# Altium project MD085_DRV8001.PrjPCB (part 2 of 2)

## Sheet MD085_TCAN284x.SchDoc: TCAN284x-Q1
size 431 x 279 mm; Date: Not shown in title block; ApprovedBy: Not shown in title block; CheckedBy: Not shown in title block; Author: Not shown in title block; CompanyName: Not shown in title block; DrawnBy: Keerthi Kumanan; Engineer: Not shown in title block; Organization: Not shown in title block; Address1: Not shown in title block; Address2: Not shown in title block; Address3: Not shown in title block; Address4: Not shown in title block; DocumentNumber: 1; Revision: Use project parameter SCH_Rev; SheetNumber: 5; SheetTotal: 1; PageSetup: Record=PageOptions¦CenterHorizontal=True¦CenterVertical=True¦PrintScale=1.00¦XCorrection=1.00¦YCorrection=1.00¦PrintKind=0¦BorderSize=5000000¦LeftOffset=0¦BottomOffset=0¦Orientation=2¦PaperLength=1000¦PaperWidth=1000¦Scale=100¦PaperSource=15¦PrintQuality=600¦MediaType=1¦DitherType=10¦PaperKind=Letter¦PrintScaleMode=1

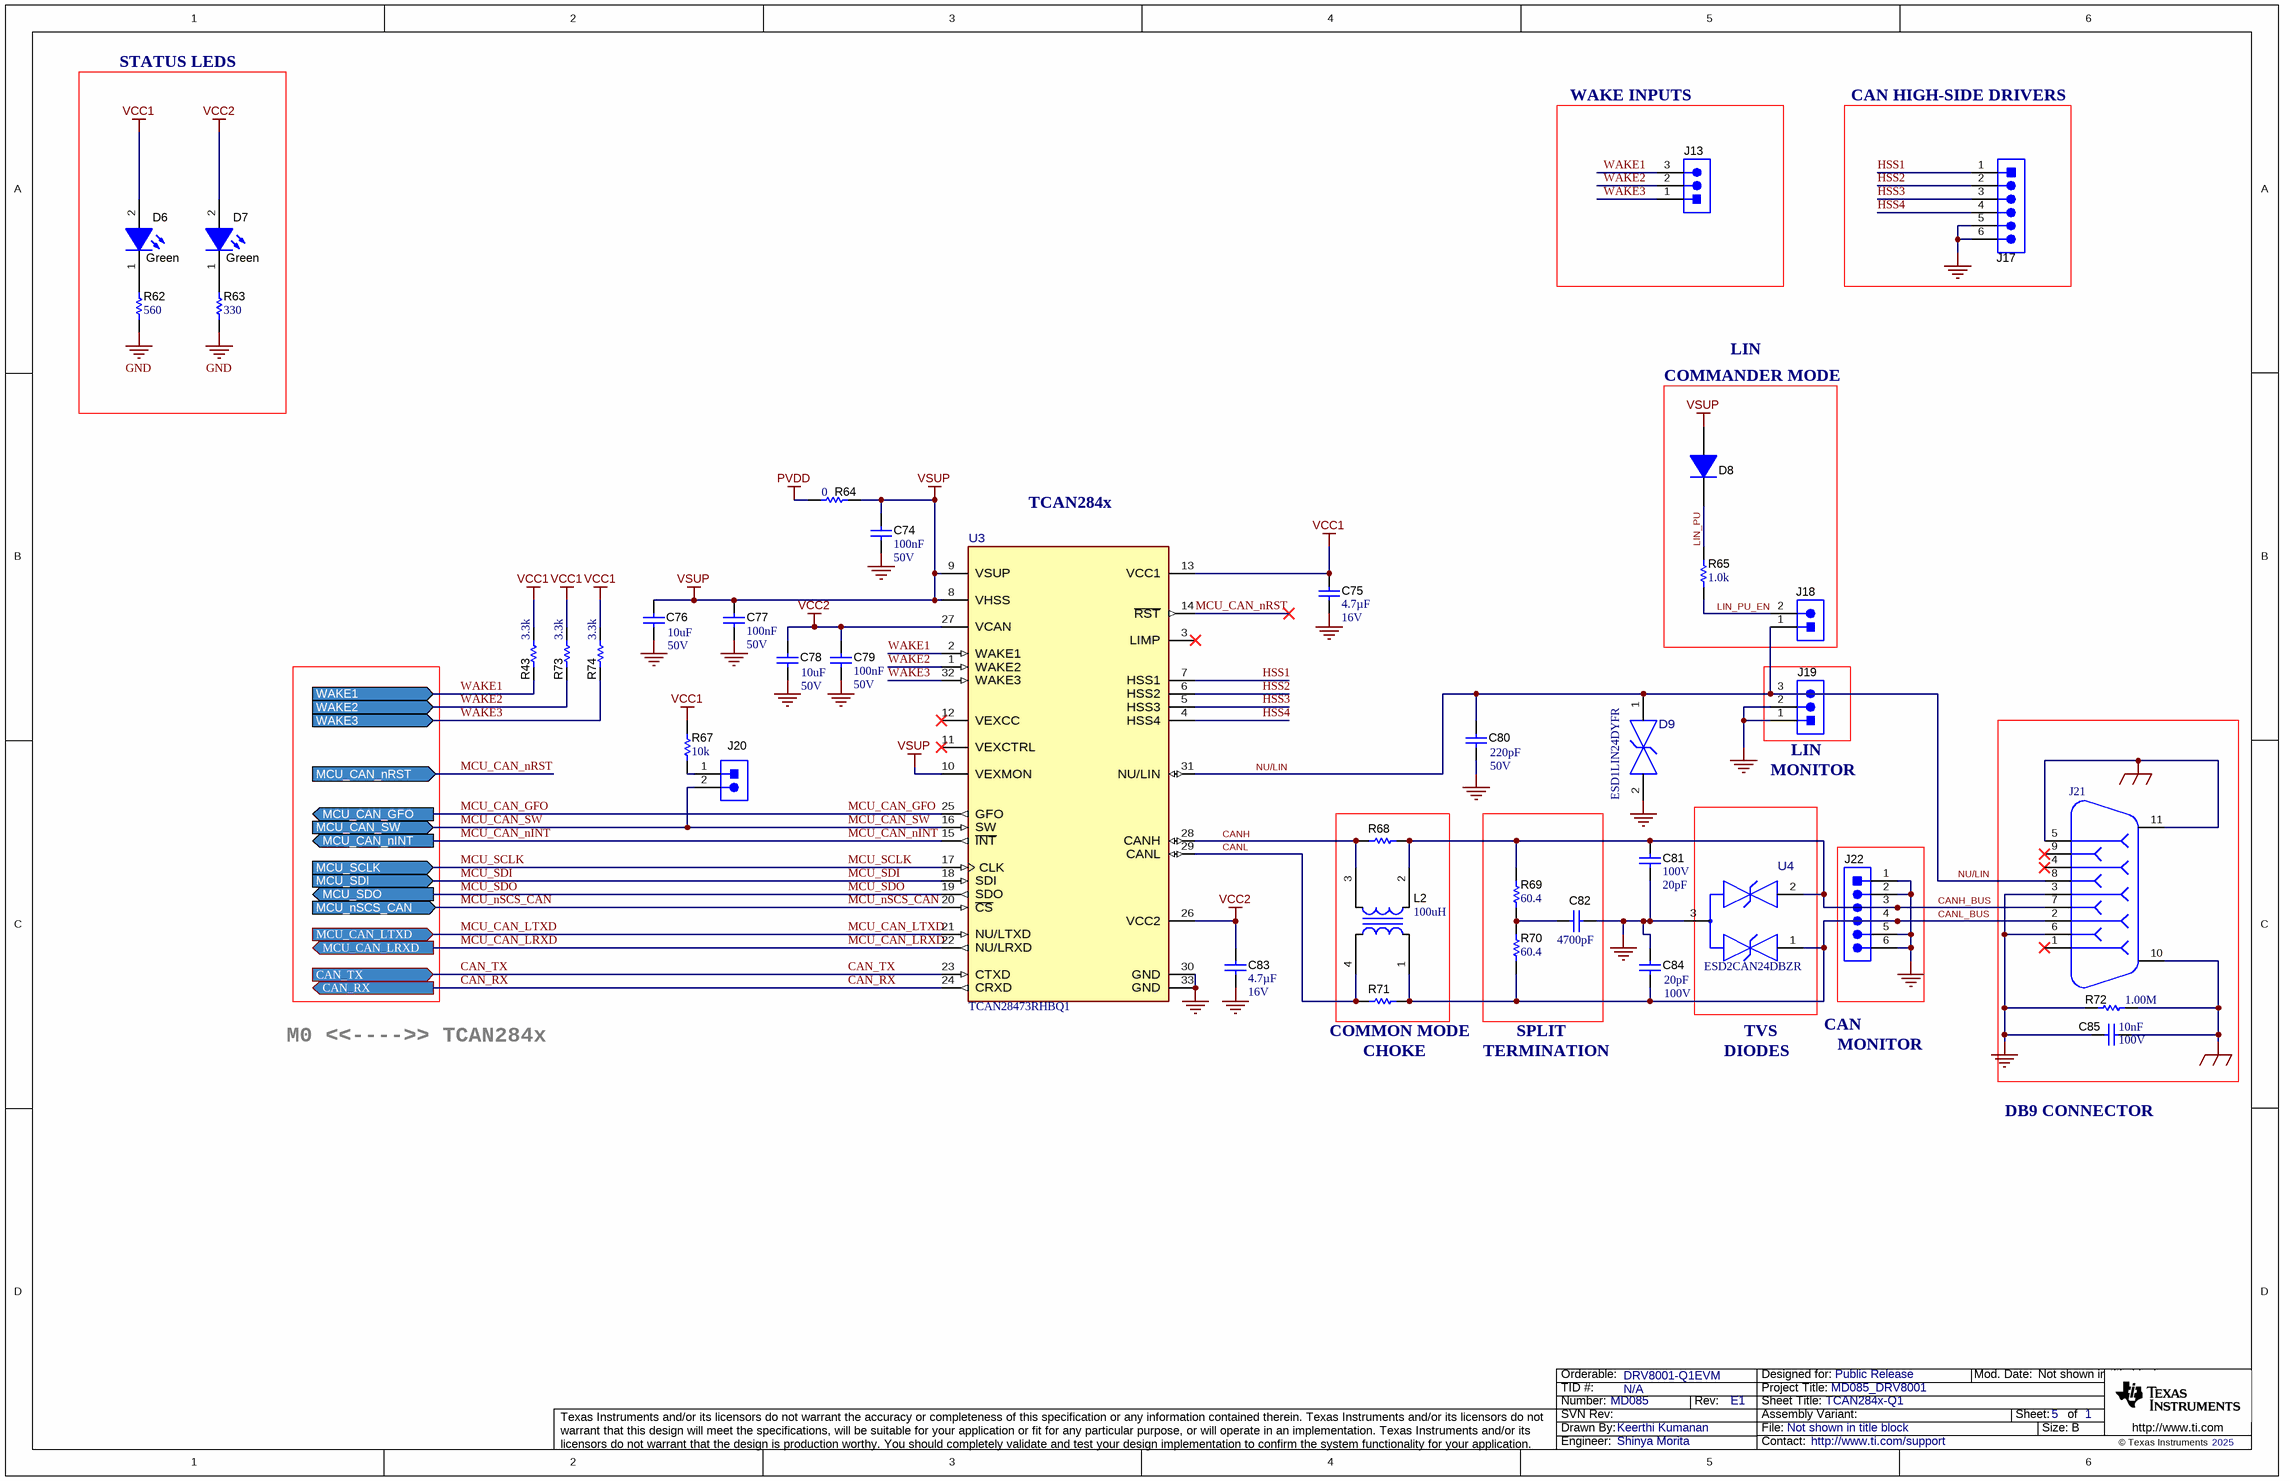
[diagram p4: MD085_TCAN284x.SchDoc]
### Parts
C74  Cap_F: 100nF  VDC_V: 50V  [0603S]  (hidden comment: C1608X7R1H104K080AA)
C75  Cap_F: 4.7µF  VDC_V: 16V  [0805L]  (hidden comment: CGA4J3X7R1C475K125AE)
C76  VDC_V: 50V  ValueDisplayed: 10uF  [1206_180]  (hidden comment: CL31B106KBHNNNE)
C77  Cap_F: 100nF  VDC_V: 50V  [0603S]  (hidden comment: C1608X7R1H104K080AA)
C78  VDC_V: 50V  ValueDisplayed: 10uF  [1206_180]  (hidden comment: CL31B106KBHNNNE)
C79  Cap_F: 100nF  VDC_V: 50V  [0603S]  (hidden comment: C1608X7R1H104K080AA)
C80  Value2: 50V  ValueDisplayed: 220pF  [0603S]  (hidden comment: 06035A221FAT2A)
C81  VDC_V: 100V  ValueDisplayed: 20pF  [0603S]  (hidden comment: GRM1885C2A200JA01D)
C82  ValueDisplayed: 4700pF  [0603S]  (hidden comment: 06031C472KAT2A)
C83  Cap_F: 4.7µF  VDC_V: 16V  [0805L]  (hidden comment: CGA4J3X7R1C475K125AE)
C84  VDC_V: 100V  ValueDisplayed: 20pF  [0603S]  (hidden comment: GRM1885C2A200JA01D)
C85  Cap_F: 10nF  VDC_V: 100V  [0603S]  (hidden comment: C0603X103K1RACTU)
D6  value Green  [WL-SMCW_GREEN]  (hidden comment: 150060VS75000)
D7  value Green  [WL-SMCW_GREEN]  (hidden comment: 150060VS75000)
D8  1N4148W-TP  [SOD-123]  (value not drawn)
D9  ESD1LIN24DYFR  [DYF0002A-MFG]
J13  TSW-103-07-G-S  [TSW-103-07-G-S]  (value not drawn)
J17  TSW-106-07-G-S  [TSW-106-07-G-S]  (value not drawn)
J18  TSW-102-07-G-S  [TSW-102-07-G-S]  (value not drawn)
J19  TSW-103-07-G-S  [TSW-103-07-G-S]  (value not drawn)
J20  TSW-102-07-G-S  [TSW-102-07-G-S]  (value not drawn)
J21  190-009-263R001  [NORCOMP_190-009-263R001]  (value not drawn)
J22  TSW-106-07-G-S  [TSW-106-07-G-S]  (value not drawn)
L2  ValueDisplayed: 100uH  [ACT45B_NoSilk]  (hidden comment: ACT45B-101-2P-TL003)
R43  ValueDisplayed: 3.3k  [0603]  (hidden comment: RC0603JR-073K3L)
R62  ValueDisplayed: 560  [0603]  (hidden comment: RC0603JR-07560RL)
R63  ValueDisplayed: 330  [0603]  (hidden comment: RC0603JR-07330RL)
R64  value 0  [0603]  (hidden comment: Resistor)
R65  ValueDisplayed: 1.0k  [0603]  (hidden comment: RC0603JR-071KL)
R67  ValueDisplayed: 10k  [0603]  (hidden comment: RC0603JR-0710KL)
R68  RC0603JR-070RL  [0603]  (value not drawn)
R69  ValueDisplayed: 60.4  [0603S]  (hidden comment: RC0603FR-0760R4L)
R70  ValueDisplayed: 60.4  [0603S]  (hidden comment: RC0603FR-0760R4L)
R71  RC0603JR-070RL  [0603]  (value not drawn)
R72  ValueDisplayed: 1.00M  [0402S]  (hidden comment: ERJ-2RKF1004X)
R73  ValueDisplayed: 3.3k  [0603]  (hidden comment: RC0603JR-073K3L)
R74  ValueDisplayed: 3.3k  [0603]  (hidden comment: RC0603JR-073K3L)
U3  TCAN28473RHBQ1  [RHB0032U-MFG]
U4  ESD2CAN24DBZR  [DBZ0003A-MFG]

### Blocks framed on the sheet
STATUS LEDS: D6 D7 R62 R63
WAKE INPUTS: J13
CAN HIGH-SIDE DRIVERS: J17
COMMANDER MODE: D8 J18 R65

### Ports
CAN_RX (out), CAN_TX (in), MCU_CAN_GFO (out), MCU_CAN_LRXD (out), MCU_CAN_LTXD (in), MCU_CAN_nINT (out), MCU_CAN_nRST (in), MCU_CAN_SW (in), MCU_nSCS_CAN (in), MCU_SCLK (in), MCU_SDI (in), MCU_SDO (out), WAKE1 (in), WAKE2 (in), WAKE3 (in)

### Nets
GND: C74.2 C75.2 C76.2 C77.2 C78.2 C79.2 C80.2 C81.2 C82.1 C83.2 C84.1 C85.2 D9.2(GND) J17.5 J17.6 J19.1 J19.2 J21.3 J21.6 J22.1 J22.2 J22.5 J22.6 R62.1 R63.1 R72.1 U3.30(GND) U3.33(GND) U4.3(GND)
PVDD: R64.2
SHIELD_GND: C85.1 J21.5 J21.10 J21.11 R72.2
VCC1: C75.1 D6.2(A) R43.2 R67.2 R73.2 R74.2 U3.13(VCC1)
VCC2: C78.1 C79.1 C83.1 D7.2(A) U3.26(VCC2) U3.27(VCAN)
VSUP: C74.1 C76.1 C77.1 D8.2(A) R64.1 U3.8(VHSS) U3.9(VSUP) U3.10(VEXMON)
CAN_RX: U3.24(CRXD) ; port CAN_RX
CAN_TX: U3.23(CTXD) ; port CAN_TX
CANH: L2.3 R68.1 U3.28(CANH)
CANH_BUS: C81.1 J21.7 J22.3 L2.2 R68.2 R69.2 U4.2(2_IO)
CANL: L2.4 R71.1 U3.29(CANL)
CANL_BUS: C84.2 J21.2 J22.4 L2.1 R70.1 R71.2 U4.1(1_IO)
HSS1: J17.1 U3.7(HSS1)
HSS2: J17.2 U3.6(HSS2)
HSS3: J17.3 U3.5(HSS3)
HSS4: J17.4 U3.4(HSS4)
LIN_PU: D8.1(K) R65.1
LIN_PU_EN: J18.2 R65.2
MCU_CAN_GFO: U3.25(GFO) ; port MCU_CAN_GFO
MCU_CAN_LRXD: U3.22(NU/LRXD) ; port MCU_CAN_LRXD
MCU_CAN_LTXD: U3.21(NU/LTXD) ; port MCU_CAN_LTXD
MCU_CAN_nINT: U3.15(~{INT}) ; port MCU_CAN_nINT
MCU_CAN_nRST: U3.14(~{RST}) ; port MCU_CAN_nRST
MCU_CAN_SW: J20.2 U3.16(SW) ; port MCU_CAN_SW
MCU_nSCS_CAN: U3.20(~{CS}) ; port MCU_nSCS_CAN
MCU_SCLK: U3.17(CLK) ; port MCU_SCLK
MCU_SDI: U3.18(SDI) ; port MCU_SDI
MCU_SDO: U3.19(SDO) ; port MCU_SDO
NU/LIN: C80.1 D9.1(IO) J18.1 J19.3 J21.8 U3.31(NU/LIN)
WAKE1: J13.3 R43.1 U3.2(WAKE1) ; port WAKE1
WAKE2: J13.2 R73.1 U3.1(WAKE2) ; port WAKE2
WAKE3: J13.1 R74.1 U3.32(WAKE3) ; port WAKE3
NetC82_2: C82.2 R69.1 R70.2
NetD6_1: D6.1(K) R62.2
NetD7_1: D7.1(K) R63.2
NetJ20_1: J20.1 R67.1

Not connected (* = marked no-connect by the designer): J21 1* 4* 9*; U3 3(LIMP)* 11(VEXCTRL)* 12(VEXCC)*

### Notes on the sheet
- LIN
- TCAN284x
- (near J19) LIN
- (near J19) MONITOR
- CAN
- M0 <<---->> TCAN284x
- (near R71) COMMON MODE
- (near R71) CHOKE
- TERMINATION
- SPLIT
- DIODES
- TVS
- MONITOR
- DB9 CONNECTOR

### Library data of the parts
C74 C77 C79 = CMP-0007044-5: CAP, CERM, 0.1 uF, 50 V, +/- 10%, X7R, 0603; Manufacturer: TDK; TaMin_C: -55°C; ESR_ohm: 29.6m; Polarized: N; SizeAreaWB_mm2: 4.68; Value1: 0.0296 ohm; U/M: EA; Value: 0.1uF; TaMax_C: 125°C; SizeZ_mm: 1; SizeX_mm: 1.6; SizeY_mm: 0.8; Cap_Case: 0603; SizeArea_mm2: 1.28; IRMS_A: 971.99mA; AEC Category: Q200
C75 C83 = CMP-0080701-1: CAP, CERM, 4.7 µF, 16 V,+/- 10%, X7R, AEC-Q200 Grade 1, 0805; Manufacturer: TDK; SizeAreaWB_mm2: 6.75; SizeArea_mm2: 2.5; AEC Qualified: Y; AEC Category: Q200; Value: 4.7uF; TaMax_C: 125°C; SizeZ_mm: 1.45; AEC Grade: 1; Polarized: N; TaMin_C: -55°C; SizeY_mm: 1.25; U/M: EA; SizeX_mm: 2; Cap_Case: 0805
C76 C78 = CMP-0008802-2: CAP, CERM, 10 uF, 50 V, +/- 10%, X7R, 1206; Manufacturer: Samsung; TaMin_C: -55°C; Polarized: N; SizeAreaWB_mm2: 10.92; Value1: Unknown; U/M: EA; Value: 10uF; TaMax_C: 125°C; SizeZ_mm: 1.8; SizeX_mm: 3.2; SizeY_mm: 1.6; Cap_Case: 1206; SizeArea_mm2: 5.12; Cap_F: 10µF; AEC Category: Q200
C80 = CMP-0006776-4: CAP, CERM, 220 pF, 50 V, +/- 1%, C0G/NP0, 0603; Manufacturer: AVX; TaMin_C: -55°C; ESR_ohm: 83m; Polarized: N; SizeAreaWB_mm2: 4.68; Value1: 0.083 ohm; U/M: EA; Value: 220pF; TaMax_C: 125°C; SizeZ_mm: 1; SizeX_mm: 1.6; SizeY_mm: 0.8; Cap_Case: 0603; SizeArea_mm2: 1.28; AEC Category: Q200
C81 C84 = CMP-0007253-4: CAP, CERM, 20 pF, 100 V, +/- 5%, C0G/NP0, 0603; Manufacturer: MuRata; TaMin_C: -55°C; Polarized: N; SizeAreaWB_mm2: 4.68; Value1: Unknown; U/M: EA; Value: 20pF; TaMax_C: 125°C; SizeZ_mm: 1; SizeX_mm: 1.6; SizeY_mm: 0.8; Cap_Case: 0603; SizeArea_mm2: 1.28; AEC Category: Q200
C82 = CMP-0006746-5: CAP, CERM, 4700 pF, 100 V, +/- 10%, X7R, 0603; Manufacturer: AVX; TaMin_C: -55°C; ESR_ohm: 0.136; Polarized: N; SizeAreaWB_mm2: 4.68; Value1: 0.136 ohm; U/M: EA; Value: 4700pF; TaMax_C: 125°C; SizeZ_mm: 1; SizeX_mm: 1.6; SizeY_mm: 0.8; Cap_Case: 0603; Value2: 100V; SizeArea_mm2: 1.28; Cap_F: 4.7nF; AEC Category: Q200
C85 = CMP-0006977-4: CAP, CERM, 0.01 uF, 100 V, +/- 10%, X7R, 0603; Manufacturer: Kemet; TaMin_C: -55°C; Polarized: N; SizeAreaWB_mm2: 4.68; Value1: Unknown; U/M: EA; Value: 0.01uF; TaMax_C: 125°C; SizeZ_mm: 1; SizeX_mm: 1.6; SizeY_mm: 0.8; Cap_Case: 0603; SizeArea_mm2: 1.28; AEC Category: Q200
D6 D7 = CMP-0002894-2: LED, Green, SMD; Manufacturer: Wurth Elektronik; Type: AlInGaP; Value2: 2V; Io_A: 20mA; Value1: W
D8 = CMP-0076974-2: Diode, Switching, 100 V, 0.15 A, SOD-123; Manufacturer: Micro Commercial Components; SizeAreaWB_mm2: 13.095; Vr_V: 100V; SizeArea_mm2: 6.545; TJmax_C: 150°C; AEC Category: Q101; Value: 100V; SizeZ_mm: 1.35; Green_REACh: Incomplete; Io_A: 150mA; Vf_V: 1.25V; SizeY_mm: 1.7; Green_Lifecycle: Not Set; Value1: 0.15A; SizeX_mm: 3.85
D9 = CMP-0098376-1: 24-V, 1-Channel ESD Protection Diode; Manufacturer: Texas Instruments; AEC Qualified: No; SizeZ_mm: 1mm; VRWM: 24V; Ipp: 16A; Ppk: 159.1W; Breakdown Voltage: 25.5V; Cap_F: 2.3pF; Clamping Voltage: 40V; Direction: Bidirectional; Number Of Channels: 1; Standoff Height: 0mm; TaMax_C: +150°C; TaMin_C: -55°C
J13 J19 = CMP-0075407-2: Header, 100mil, 3x1, Gold, TH; Manufacturer: Samtec; Pitch_mm: 2.54; Gender: Male; Cert_CSA: Y; Row_Count: 1; Cert_CULUS: N; Current_A: 6.3A; Green_Lifecycle: Active; Green_REACh: Passed; Voltage_V: 550V
J17 J22 = CMP-0075413-2: Header, 100mil, 6x1, Gold, TH; Manufacturer: Samtec; Pitch_mm: 2.54; Cert_VDE: N; Gender: Male; Cert_CSA: Y; Voltage_V: 550V; Green_REACh: Passed; Current_A: 6.3A; Green_Lifecycle: Active; Row_Count: 1
J18 J20 = CMP-0075405-3: Header, 100mil, 2x1, Gold, TH; Manufacturer: Samtec; Pitch_mm: 2.54; Gender: Male; Cert_CSA: Y; Row_Count: 1; Cert_CULUS: N; Current_A: 6.3A; Green_Lifecycle: Active; Green_REACh: Passed; Voltage_V: 550V
J21 = CMP-0074875-1: Receptacle, D-Sub, 9 Position, R/A, SMT; Manufacturer: NorComp; CNHeader: False; Green_Lifecycle: Not Set; Gender: Female; Green_REACh: Incomplete; Row_Count: 2; ContactFinish: Gold; CT: True
L2 = CMP-0062430-2: Inductor, Ferrite, 100 uH, 0.15 A, 2 ohm, SMD; Manufacturer: TDK; Isat: 0.15A @ % inductance drop; Green_Lifecycle: Active; SizeAreaWB_mm2: 23.1; DCR_ohm: 2; Green_REACh: Passed; Value1: 2 ohm; Value: 100uH; Imax_A: 150mA; SizeZ_mm: 3; SizeX_mm: 4.5; SizeY_mm: 3.2; Value2: 0.15A; SizeArea_mm2: 14.4; Ind_H: 100µH; AEC Category: Q200
R43 R73 R74 = CMP-0025918-5: RES, 3.3 k, 5%, 0.1 W, 0603; Manufacturer: Yageo; Power_W: 100mW; TempCo: 100 ppm/C; Value_Code: 3k30; Value: 3.3k; SizeX_mm: 1.6; SizeY_mm: 0.8; SizeZ_mm: 1; Value2: 0.1W; SizeArea_mm2: 1.28; AEC Qualified: N; VDC_V: 75V; AEC Category: Q200; EIA_Code: E24; SizeAreaWB_mm2: 4.68
R62 = CMP-0025930-5: RES, 560, 5%, 0.1 W, 0603; Manufacturer: Yageo; Power_W: 100mW; TempCo: 100 ppm/C; Value_Code: 560R; Value: 560; EIA_Code: E24; SizeX_mm: 1.6; SizeY_mm: 0.8; SizeZ_mm: 1; Value2: 0.1W; SizeArea_mm2: 1.28; AEC Qualified: N; VDC_V: 75V; AEC Category: Q200; SizeAreaWB_mm2: 4.68
R63 = CMP-0025912-5: RES, 330, 5%, 0.1 W, 0603; Manufacturer: Yageo; Power_W: 100mW; TempCo: 100 ppm/C; Value_Code: 330R; Value: 330; EIA_Code: E24; SizeX_mm: 1.6; SizeY_mm: 0.8; SizeZ_mm: 1; Value2: 0.1W; SizeArea_mm2: 1.28; AEC Qualified: N; VDC_V: 75V; AEC Category: Q200; SizeAreaWB_mm2: 4.68
R64 = CMP-0025885-5: RES, 0, 5%, 0.1 W, 0603; PartNumber: RC0603JR-070RL; Manufacturer: Yageo; Power_W: 100mW; VDC_V: 75V; AEC Qualified: N; SizeZ_mm: 1; AEC Category: Q200; EIA_Code: E24; SizeArea_mm2: 1.28; SizeAreaWB_mm2: 4.68; SizeX_mm: 1.6; SizeY_mm: 0.8; TempCo: 200 ppm/C; Value2: 0.1W; Value_Code: 0000
R65 = CMP-0025899-5: RES, 1.0 k, 5%, 0.1 W, 0603; Manufacturer: Yageo; Power_W: 100mW; TempCo: 100 ppm/C; Value_Code: 1k00; Value: 1.0k; EIA_Code: E24; Res_ohm: 1k; SizeX_mm: 1.6; SizeY_mm: 0.8; SizeZ_mm: 1; Value2: 0.1W; SizeArea_mm2: 1.28; AEC Qualified: N; VDC_V: 75V; AEC Category: Q200; SizeAreaWB_mm2: 4.68
R67 = CMP-0025886-5: RES, 10 k, 5%, 0.1 W, 0603; Manufacturer: Yageo; Value: 10k; SizeY_mm: 0.8; SizeArea_mm2: 1.28; EIA_Code: E24; Power_W: 100mW; SizeX_mm: 1.6; Value2: 0.1W; Value_Code: 10k0; VDC_V: 75V; SizeZ_mm: 1; AEC Qualified: N; AEC Category: Q200; TempCo: 100 ppm/C; SizeAreaWB_mm2: 4.68
R68 R71 = CMP-0025885-5: RES, 0, 5%, 0.1 W, 0603; Manufacturer: Yageo; AEC Qualified: N; Res_ohm: 0; Value: 0; SizeZ_mm: 1; Power_W: 100mW; VDC_V: 75V; AEC Category: Q200; EIA_Code: E24; SizeArea_mm2: 1.28; SizeAreaWB_mm2: 4.68; SizeX_mm: 1.6; SizeY_mm: 0.8; TempCo: 200 ppm/C; Value2: 0.1W; Value_Code: 0000
R69 R70 = CMP-0023213-5: RES, 60.4, 1%, 0.1 W, 0603; Manufacturer: Yageo; Power_W: 100mW; TempCo: 100 ppm/C; Value_Code: 60R4; Value: 60.4; EIA_Code: E96; SizeX_mm: 1.6; SizeY_mm: 0.8; SizeZ_mm: 1; Value2: 0.1W; SizeArea_mm2: 1.28; AEC Qualified: N; VDC_V: 75V; AEC Category: Q200; SizeAreaWB_mm2: 4.68
R72 = CMP-0026660-1: RES, 1.00 M, 1%, 0.1 W, 0402; Manufacturer: Panasonic; Power_W: 100mW; TempCo: 100 ppm/C; Value_Code: 1M00; U/M: EA; Value: 1.00Meg; EIA_Code: E96; Res_ohm: 1M; SizeX_mm: 1; SizeY_mm: 0.5; SizeZ_mm: 0.6; Value2: 0.1W; VDC_V: 50V; AEC Category: Q200
U3 = CMP-0093295-1: CAN FD and LIN System Basis Chip (SBC) with Integrated Watchdog, Selective Wake and Advanced CAN Bus Fault Diagnostics; Manufacturer: Texas Instruments; TJmax_C: +150°C; Min Supply Voltage: 4.5V; Interface: SPI,CAN,LIN; Standoff Height: 0mm; AEC Grade: Grade 1; SizeZ_mm: 1mm; Max Supply Voltage: 28V; AEC Qualified: Yes
U4 = CMP-0093261-1: 24-V, 2-Channel ESD Protection Diode for In-Vehicle Networks; Manufacturer: Texas Instruments; Cap_F: 3pF; Breakdown Voltage: 25.5V; Clamping Voltage: 32V; TaMax_C: +150°C; Direction: Bidirectional; TaMin_C: -55°C; Ipp: 3.5A; VRWM: 24V; Standoff Height: 0.01mm; SizeZ_mm: 1.12mm; Ppk: 147W; AEC Qualified: No; Number Of Channels: 2

## Sheet MD085_DRV800x.SchDoc: DRV800x-Q1
size 431 x 279 mm; VersionControl_RevNumber: 1; Date: Not shown in title block; ApprovedBy: Not shown in title block; CheckedBy: Not shown in title block; Author: Not shown in title block; CompanyName: Not shown in title block; DrawnBy: Keerthi Kumanan; Engineer: Not shown in title block; Organization: Not shown in title block; Address1: Not shown in title block; Address2: Not shown in title block; Address3: Not shown in title block; Address4: Not shown in title block; DocumentNumber: 1; Revision: 1; SheetNumber: 4; SheetTotal: 1; PageSetup: Record=PageOptions¦CenterHorizontal=True¦CenterVertical=True¦PrintScale=1.00¦XCorrection=1.00¦YCorrection=1.00¦PrintKind=0¦BorderSize=5000000¦LeftOffset=0¦BottomOffset=0¦Orientation=2¦PaperLength=1000¦PaperWidth=1000¦Scale=100¦PaperSource=15¦PrintQuality=600¦MediaType=1¦DitherType=10¦PaperKind=Letter¦PrintScaleMode=1; VersionControl_ProjFolderRevNumber: 1; VersionControl_RevNumberShort: 1; VersionControl_ProjFolderRevNumberShort: 1

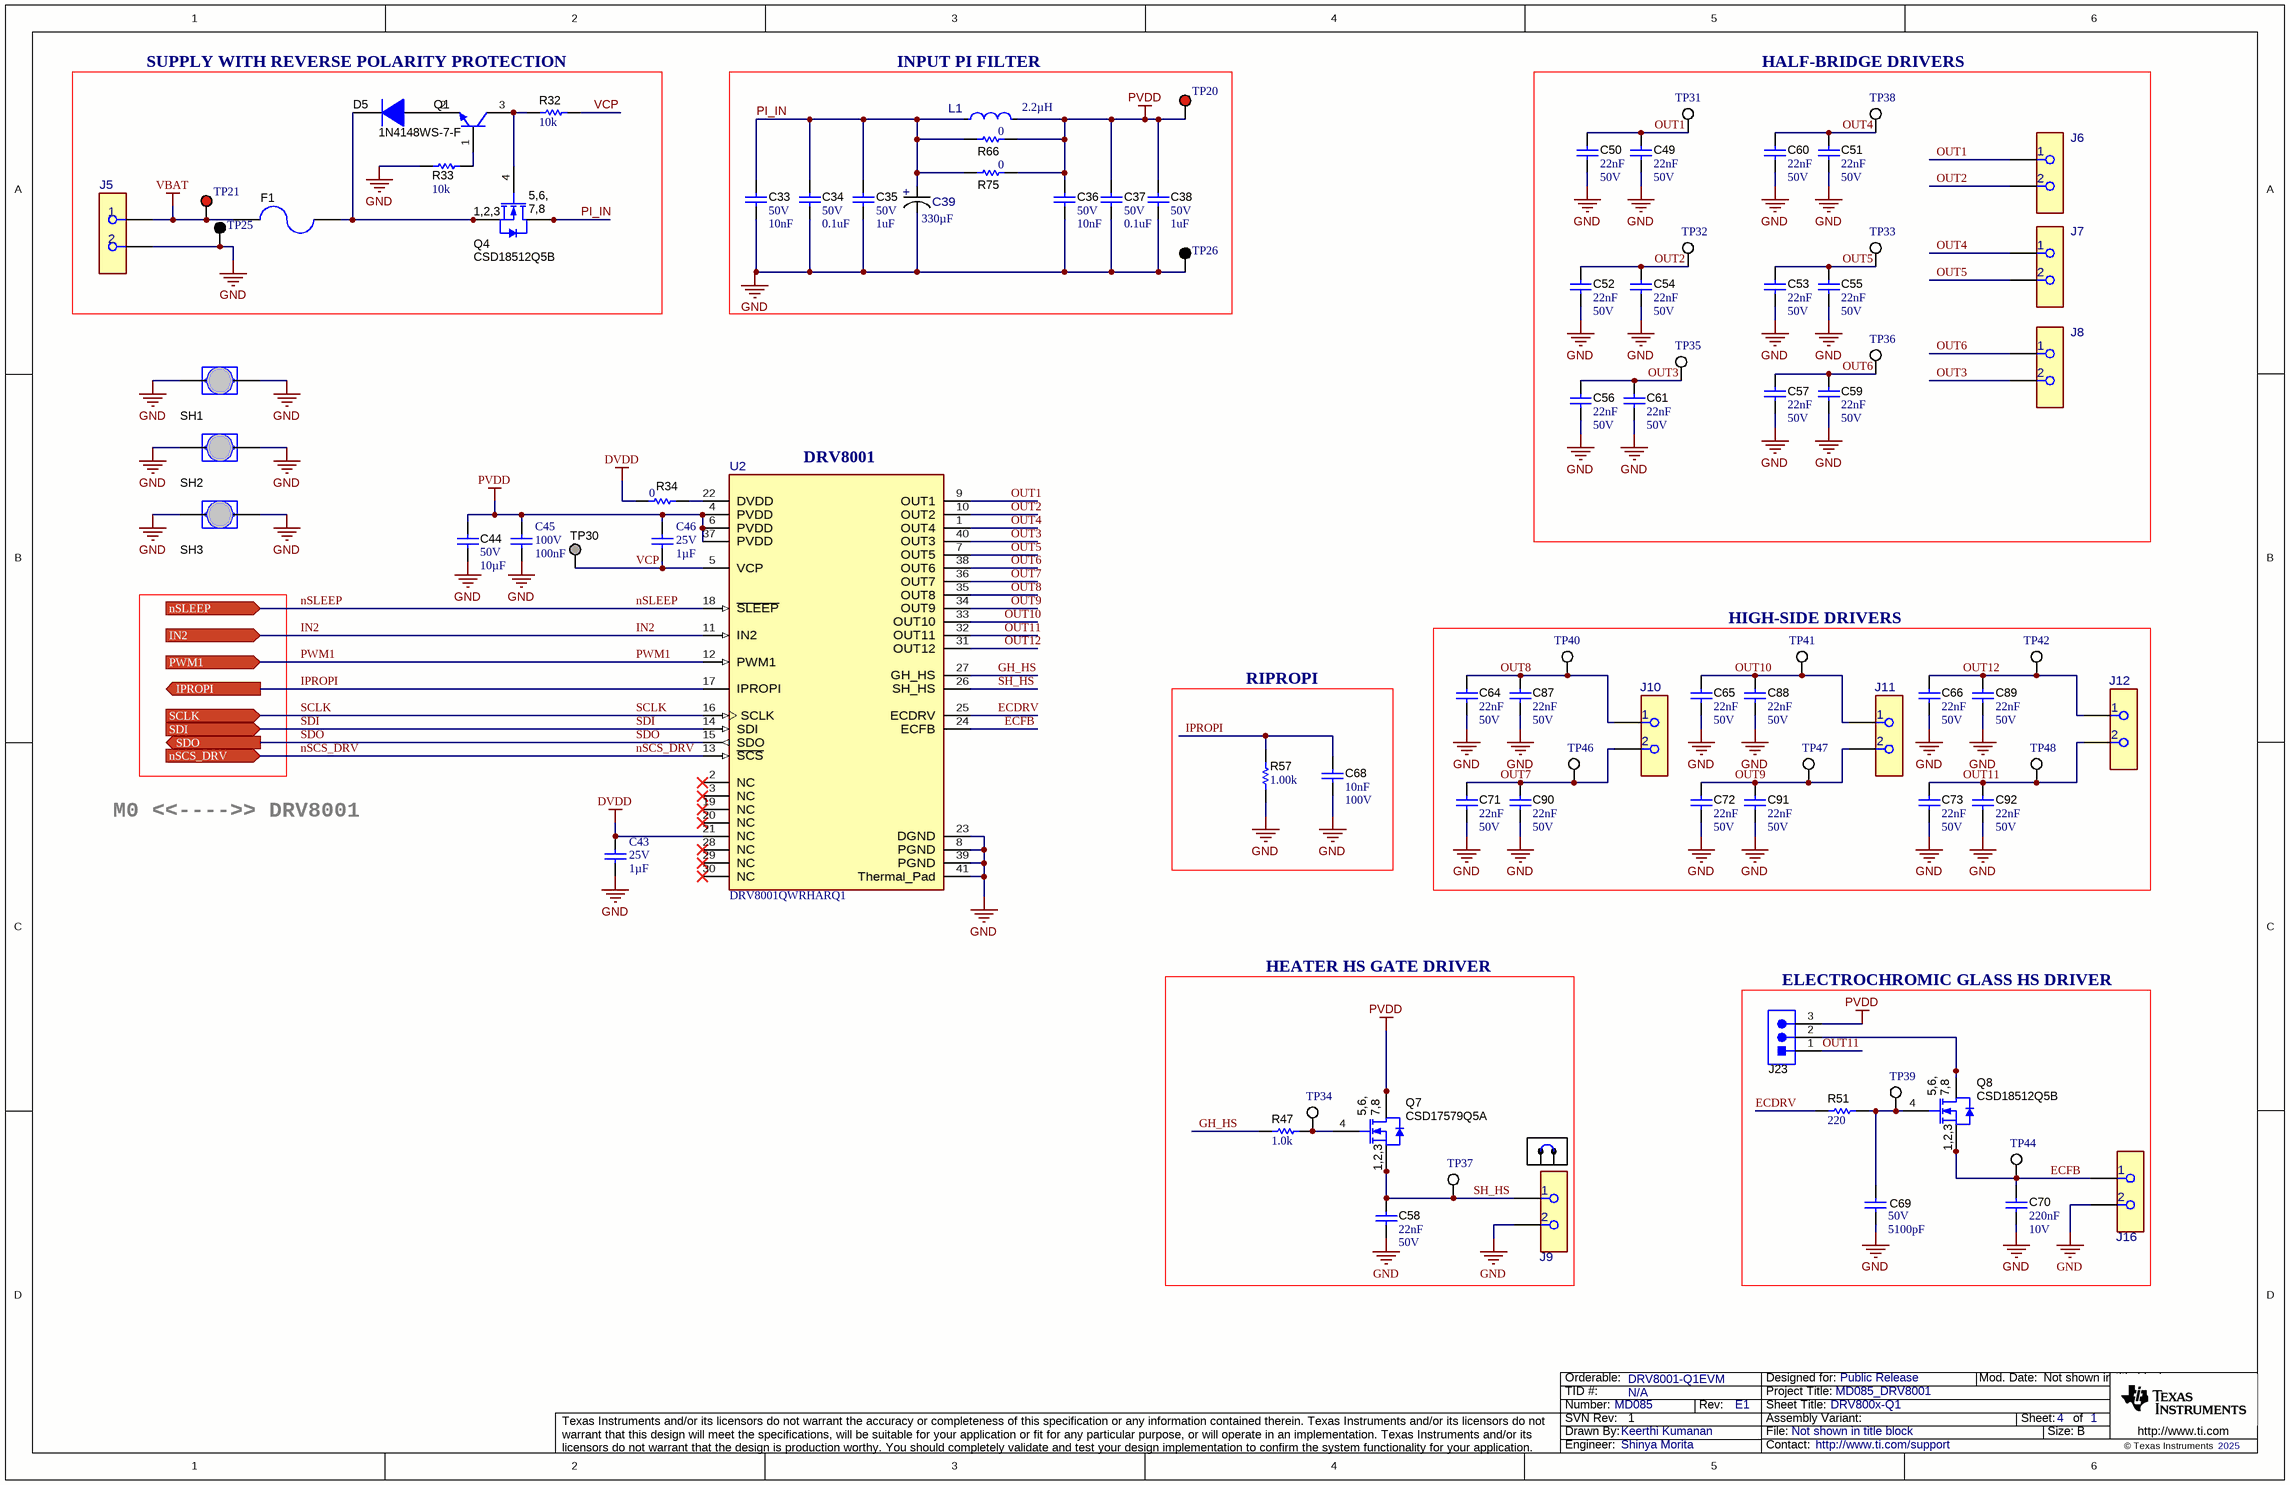
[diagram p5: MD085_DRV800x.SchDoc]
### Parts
C33  VDC_V: 50V  Cap_F: 10nF  [0603L]  (hidden comment: 885012206089)
C34  VDC_V: 50V  ValueDisplayed: 0.1uF  [0603]  (hidden comment: 885012206095)
C35  VDC_V: 50V  ValueDisplayed: 1uF  [0805L]  (hidden comment: 885012207103)
C36  VDC_V: 50V  Cap_F: 10nF  [0603L]  (hidden comment: 885012206089)
C37  VDC_V: 50V  ValueDisplayed: 0.1uF  [0603]  (hidden comment: 885012206095)
C38  VDC_V: 50V  ValueDisplayed: 1uF  [0805L]  (hidden comment: 885012207103)
C39  Cap_F: 330µF  [FP-860020675021_RADIAL-MFG]  (hidden comment: 860020675021)
C43  value 1µF  Rated Voltage (DC): 25V  [WCAP-CSGP_0603_L1.6W0.8H0.8_Reflow]  (hidden comment: 885012206076)
C44  VDC_V: 50V  ValueDisplayed: 10µF  [1206_180]  (hidden comment: 885012108022)
C45  value 100nF  Rated Voltage (DC): 100V  [WCAP-CSGP_0603_L1.6W0.8H0.8_Reflow]  (hidden comment: 885012206120)
C46  value 1µF  Rated Voltage (DC): 25V  [WCAP-CSGP_0603_L1.6W0.8H0.8_Reflow]  (hidden comment: 885012206076)
C49  Cap_F: 22nF  VDC_V: 50V  [0603]  (hidden comment: 885012206091)
C50  Cap_F: 22nF  VDC_V: 50V  [0603]  (hidden comment: 885012206091)
C51  Cap_F: 22nF  VDC_V: 50V  [0603]  (hidden comment: 885012206091)
C52  Cap_F: 22nF  VDC_V: 50V  [0603]  (hidden comment: 885012206091)
C53  Cap_F: 22nF  VDC_V: 50V  [0603]  (hidden comment: 885012206091)
C54  Cap_F: 22nF  VDC_V: 50V  [0603]  (hidden comment: 885012206091)
C55  Cap_F: 22nF  VDC_V: 50V  [0603]  (hidden comment: 885012206091)
C56  Cap_F: 22nF  VDC_V: 50V  [0603]  (hidden comment: 885012206091)
C57  Cap_F: 22nF  VDC_V: 50V  [0603]  (hidden comment: 885012206091)
C58  Cap_F: 22nF  VDC_V: 50V  [0603]  (hidden comment: 885012206091)
C59  Cap_F: 22nF  VDC_V: 50V  [0603]  (hidden comment: 885012206091)
C60  Cap_F: 22nF  VDC_V: 50V  [0603]  (hidden comment: 885012206091)
C61  Cap_F: 22nF  VDC_V: 50V  [0603]  (hidden comment: 885012206091)
C64  Cap_F: 22nF  VDC_V: 50V  [0603]  (hidden comment: 885012206091)
C65  Cap_F: 22nF  VDC_V: 50V  [0603]  (hidden comment: 885012206091)
C66  Cap_F: 22nF  VDC_V: 50V  [0603]  (hidden comment: 885012206091)
C68  Cap_F: 10nF  VDC_V: 100V  [0603]  (hidden comment: 885012206114)
C69  VDC_V: 50V  ValueDisplayed: 5100pF  [0603]  (hidden comment: C0603C512J5GAC7867)
C70  Cap_F: 220nF  VDC_V: 10V  [0603]  (hidden comment: 885012206022)
C71  Cap_F: 22nF  VDC_V: 50V  [0603]  (hidden comment: 885012206091)
C72  Cap_F: 22nF  VDC_V: 50V  [0603]  (hidden comment: 885012206091)
C73  Cap_F: 22nF  VDC_V: 50V  [0603]  (hidden comment: 885012206091)
C87  Cap_F: 22nF  VDC_V: 50V  [0603]  (hidden comment: 885012206091)
C88  Cap_F: 22nF  VDC_V: 50V  [0603]  (hidden comment: 885012206091)
C89  Cap_F: 22nF  VDC_V: 50V  [0603]  (hidden comment: 885012206091)
C90  Cap_F: 22nF  VDC_V: 50V  [0603]  (hidden comment: 885012206091)
C91  Cap_F: 22nF  VDC_V: 50V  [0603]  (hidden comment: 885012206091)
C92  Cap_F: 22nF  VDC_V: 50V  [0603]  (hidden comment: 885012206091)
D5  1N4148WS-7-F  [SOD-323]
F1  0463030.ER  [Fuse_0463]  (value not drawn)
J5  691256610002  [FP-691256610002_HDR2-MFG]  (value not drawn)
J6  691250610002  [FP-691250610002_CONN_TERM_BLOCK2-MFG]  (value not drawn)
J7  691250610002  [FP-691250610002_CONN_TERM_BLOCK2-MFG]  (value not drawn)
J8  691250610002  [FP-691250610002_CONN_TERM_BLOCK2-MFG]  (value not drawn)
J9  691250610002  [FP-691250610002_CONN_TERM_BLOCK2-MFG]  (value not drawn)
J10  691216710002  [FP-691216710002_HDR2-MFG]  (value not drawn)
J11  691216710002  [FP-691216710002_HDR2-MFG]  (value not drawn)
J12  691216710002  [FP-691216710002_HDR2-MFG]  (value not drawn)
J16  691250610002  [FP-691250610002_CONN_TERM_BLOCK2-MFG]  (value not drawn)
J23  TSW-103-07-G-S  [TSW-103-07-G-S]  (value not drawn)
L1  Ind_H: 2.2µH  [FP-74439369022_IND_SMT_11MM6_10MM5-MFG]  (hidden comment: 74439369022)
Q1  BC846BLT1G  [SOT-23L]  (value not drawn)
Q4  CSD18512Q5B  [DNK0008A]
Q7  CSD17579Q5A  [DQJ0008A]
Q8  CSD18512Q5B  [DNK0008A]
R32  ValueDisplayed: 10k  [0603]  (hidden comment: RC0603JR-0710KL)
R33  ValueDisplayed: 10k  [0603]  (hidden comment: RC0603JR-0710KL)
R34  value 0  [0603]  (hidden comment: Resistor)
R47  ValueDisplayed: 1.0k  [0603]  (hidden comment: RC0603JR-071KL)
R51  ValueDisplayed: 220  [0603]  (hidden comment: RC0603FR-07220RL)
R57  ValueDisplayed: 1.00k  [0603]  (hidden comment: RC0603FR-071KL)
R66  ValueDisplayed: 0  [2512_084]  (hidden comment: HCJ2512ZT0R00)
R75  ValueDisplayed: 0  [2512_084]  (hidden comment: HCJ2512ZT0R00)
SH1  Jumper_2p  [Harwin_D3082-05]  (value not drawn)
SH2  Jumper_2p  [Harwin_D3082-05]  (value not drawn)
SH3  Jumper_2p  [Harwin_D3082-05]  (value not drawn)
SH-J21  60900213421  [Wurth_60900213421]  (value not drawn)
TP20  5010  [Keystone5010]  (value not drawn)
TP21  5010  [Keystone5010]  (value not drawn)
TP25  5011  [Keystone5011]  (value not drawn)
TP26  5011  [Keystone5011]  (value not drawn)
TP30  TP_H0.45P0.75  [TP_H045P075]  (value not drawn)  (no BOM)
TP31  5012  [Keystone5012]  (value not drawn)
TP32  5012  [Keystone5012]  (value not drawn)
TP33  5012  [Keystone5012]  (value not drawn)
TP34  5012  [Keystone5012]  (value not drawn)
TP35  5012  [Keystone5012]  (value not drawn)
TP36  5012  [Keystone5012]  (value not drawn)
TP37  5012  [Keystone5012]  (value not drawn)
TP38  5012  [Keystone5012]  (value not drawn)
TP39  5012  [Keystone5012]  (value not drawn)
TP40  5012  [Keystone5012]  (value not drawn)
TP41  5012  [Keystone5012]  (value not drawn)
TP42  5012  [Keystone5012]  (value not drawn)
TP44  5012  [Keystone5012]  (value not drawn)
TP46  5012  [Keystone5012]  (value not drawn)
TP47  5012  [Keystone5012]  (value not drawn)
TP48  5012  [Keystone5012]  (value not drawn)
U2  DRV8001QWRHARQ1  [RHA0040M-MFG]

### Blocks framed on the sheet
SUPPLY WITH REVERSE POLARITY PROTECTION: D5 F1 J5 Q1 Q4 R32 R33 TP21 TP25
INPUT PI FILTER: C33-C39 L1 R66 R75 TP20 TP26
HALF-BRIDGE DRIVERS: C49-C57 C59-C61 J6-J8 TP31-TP33 TP35 TP36 TP38
HIGH-SIDE DRIVERS: C64-C66 C71-C73 C87-C92 J10-J12 TP40-TP42 TP46-TP48
RIPROPI: C68 R57
HEATER HS GATE DRIVER: C58 J9 Q7 R47 SH-J21 TP34 TP37
ELECTROCHROMIC GLASS HS DRIVER: C69 C70 J16 J23 Q8 R51 TP39 TP44

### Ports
IN2 (in), IPROPI (out), nSCS_DRV (in), nSLEEP (in), PWM1 (in), SCLK (in), SDI (in), SDO (out)

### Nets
DVDD: C43.2 R34.2 U2.21(NC)
GND: C33.2 C34.2 C35.2 C36.2 C37.2 C38.2 C39.1(CATHODE) C43.1 C44.2 C45.1 C49.1 C50.1 C51.1 C52.1 C53.1 C54.1 C55.1 C56.1 C57.1 C58.1 C59.1 C60.1 C61.1 C64.1 C65.1 C66.1 C68.2 C69.2 C70.2 C71.1 C72.1 C73.1 C87.1 C88.1 C89.1 C90.1 C91.1 C92.1 J5.2 J9.2 J16.2 R33.1 R57.1 SH1.1 SH1.2 SH2.1 SH2.2 SH3.1 SH3.2 TP25.1 TP26.1 U2.8(PGND) U2.23(DGND) U2.39(PGND) U2.41(Thermal_Pad)
PVDD: C36.1 C37.1 C38.1 C44.1 C45.2 C46.2 J23.3 L1.2 Q7.5(D) Q7.6(D) Q7.7(D) Q7.8(D) Q7.9(D) R66.2 R75.2 TP20.1 U2.4(PVDD) U2.6(PVDD) U2.37(PVDD)
VBAT: F1.2 J5.1 TP21.1
ECDRV: R51.1 U2.25(ECDRV)
ECFB: C70.1 J16.1 Q8.1(S) Q8.2(S) Q8.3(S) TP44.1 U2.24(ECFB)
GH_HS: R47.2 U2.27(GH_HS)
IN2: U2.11(IN2) ; port IN2
IPROPI: C68.1 R57.2 U2.17(IPROPI) ; port IPROPI
nSCS_DRV: U2.13(~{SCS}) ; port nSCS_DRV
nSLEEP: U2.18(~{SLEEP}) ; port nSLEEP
OUT1: C49.2 C50.2 J6.1 TP31.1 U2.9(OUT1)
OUT2: C52.2 C54.2 J6.2 TP32.1 U2.10(OUT2)
OUT3: C56.2 C61.2 J8.2 TP35.1 U2.40(OUT3)
OUT4: C51.2 C60.2 J7.1 TP38.1 U2.1(OUT4)
OUT5: C53.2 C55.2 J7.2 TP33.1 U2.7(OUT5)
OUT6: C57.2 C59.2 J8.1 TP36.1 U2.38(OUT6)
OUT7: C71.2 C90.2 J10.2 TP46.1 U2.36(OUT7)
OUT8: C64.2 C87.2 J10.1 TP40.1 U2.35(OUT8)
OUT9: C72.2 C91.2 J11.2 TP47.1 U2.34(OUT9)
OUT10: C65.2 C88.2 J11.1 TP41.1 U2.33(OUT10)
OUT11: C73.2 C92.2 J12.2 J23.1 TP48.1 U2.32(OUT11)
OUT12: C66.2 C89.2 J12.1 TP42.1 U2.31(OUT12)
PI_IN: C33.1 C34.1 C35.1 C39.2(ANODE) L1.1 Q4.5(D) Q4.6(D) Q4.7(D) Q4.8(D) Q4.9(D) R66.1 R75.1
PWM1: U2.12(PWM1) ; port PWM1
SCLK: U2.16(SCLK) ; port SCLK
SDI: U2.14(SDI) ; port SDI
SDO: U2.15(SDO) ; port SDO
SH_HS: C58.2 J9.1 Q7.1(S) Q7.2(S) Q7.3(S) TP37.1 U2.26(SH_HS)
VCP: C46.1 R32.1 TP30.1 U2.5(VCP)
NetC69_1: C69.1 Q8.4(G) R51.2 TP39.1
NetD5_1: D5.1(K) F1.1 Q4.1(S) Q4.2(S) Q4.3(S)
NetD5_2: D5.2(A) Q1.2(E)
NetJ23_2: J23.2 Q8.5(D) Q8.6(D) Q8.7(D) Q8.8(D) Q8.9(D)
NetQ1_1: Q1.1(B) R33.2
NetQ1_3: Q1.3(C) Q4.4(G) R32.2
NetQ7_4: Q7.4(G) R47.1 TP34.1
NetR34_1: R34.1 U2.22(DVDD)

Not connected (* = marked no-connect by the designer): U2 2(NC)* 3(NC)* 19(NC)* 20(NC)* 28(NC)* 29(NC)* 30(NC)*

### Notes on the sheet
- (near U2) DRV8001
- M0 <<---->> DRV8001

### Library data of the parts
C33 C36 = CMP-0750039-1: CAP, CERM, 0.01 µF, 50 V,+/- 10%, X7R, 0603; Manufacturer: Wurth Elektronik; Polarized: N; AEC Category: Q200; TaMax_C: 125°C; SizeAreaWB_mm2: 4.68; Value: 0.01uF; SizeArea_mm2: 1.28; SizeY_mm: 0.8; SizeZ_mm: 1; ValueDisplayed: 0.01µF; SizeX_mm: 1.6; U/M: EA; Cap_Case: 0603; TaMin_C: -55°C
C34 C37 = CMP-0006837-4: CAP, CERM, 0.1 uF, 50 V, +/- 10%, X7R, 0603; Manufacturer: Wurth Elektronik; TaMin_C: -55°C; Polarized: N; SizeAreaWB_mm2: 4.68; Value1: Unknown; U/M: EA; Value: 0.1uF; TaMax_C: 125°C; SizeZ_mm: 1; SizeX_mm: 1.6; SizeY_mm: 0.8; SizeArea_mm2: 1.28; Cap_F: 100nF; AEC Category: Q200
C35 C38 = CMP-0007696-2: CAP, CERM, 1 uF, 50 V, +/- 10%, X7R, 0805; Manufacturer: Wurth Elektronik; TaMin_C: -55°C; Polarized: N; SizeAreaWB_mm2: 6.75; Value1: Unknown; U/M: EA; Value: 1uF; TaMax_C: 125°C; SizeZ_mm: 1.45; SizeX_mm: 2; SizeY_mm: 1.25; Cap_Case: 0805; SizeArea_mm2: 2.5; Cap_F: 1µF; AEC Category: Q200
C39 = CMP-0087013-2: Electrolytic Capacitor, 330 uF, 50 V, WCAP-ATG5 Series, 20%, Radial Leaded, 10 mm; Manufacturer: Wurth Electronics; SizeZ_mm: 17.5mm; AEC Qualified: No; IRMS_A: 450mA; ValueDisplayed: 330uF
C43 C46 = CMP-0108290-1: WCAP-CSGP Multilayer Ceramic Chip Capacitor, General Purpose, size 0603, X7R, 1µF, 25VDC; Manufacturer: Wurth Elektronik; Capacitance Tolerance: +/-10%; Case/Size Code: 0603; Dissipation Factor: 10%; Insulation Resistance: 0.5GOhm; Technical Reference: X7R0603105K025DFCT10000
C44 = CMP-0081454-1: CAP, CERM, 10 µF, 50 V,+/- 20%, X5R, 1206; Manufacturer: Wurth Elektronik; TaMin_C: -55°C; Polarized: N; SizeAreaWB_mm2: 10.92; U/M: EA; Value: 10uF; TaMax_C: 125°C; SizeZ_mm: 1.8; SizeX_mm: 3.2; SizeY_mm: 1.6; Cap_Case: 1206; SizeArea_mm2: 5.12; AEC Category: Q200
C45 = CMP-0108322-1: WCAP-CSGP Multilayer Ceramic Chip Capacitor, General Purpose, size 0603, X7R, 100nF, 100VDC; Manufacturer: Wurth Elektronik; Capacitance Tolerance: +/-10%; Case/Size Code: 0603; Dissipation Factor: 5%; Insulation Resistance: 1GOhm; Technical Reference: X7R0603104K100DFCT10000
C49-C61 C64-C66 C71-C73 C87-C92 = CMP-0006836-4: CAP, CERM, 0.022 uF, 50 V, +/- 10%, X7R, 0603; Manufacturer: Wurth Elektronik; TaMin_C: -55°C; Polarized: N; SizeAreaWB_mm2: 4.68; Value1: Unknown; U/M: EA; TaMax_C: 125°C; SizeZ_mm: 1; SizeX_mm: 1.6; SizeY_mm: 0.8; SizeArea_mm2: 1.28; AEC Category: Q200
C68 = CMP-0079993-1: CAP, CERM, 0.01 µF, 100 V,+/- 10%, X7R, 0603; Manufacturer: Wurth Elektronik; TaMin_C: -55°C; Polarized: N; SizeAreaWB_mm2: 4.68; U/M: EA; Value: 0.01uF; TaMax_C: 105°C; SizeZ_mm: 1; SizeX_mm: 1.6; SizeY_mm: 0.8; SizeArea_mm2: 1.28; AEC Category: Q200; ValueDisplayed: 0.01µF
C69 = CMP-0080094-1: CAP, CERM, 5100 pF, 50 V,+/- 5%, C0G/NP0, 0603; Manufacturer: Kemet; Cap_F: 5.1nF; SizeAreaWB_mm2: 4.68; SizeArea_mm2: 1.28; AEC Qualified: N; AEC Category: Q200; Value: 5100pF; TaMax_C: 125°C; SizeZ_mm: 1; Green_REACh: Passed; TaMin_C: -55°C; SizeY_mm: 0.8; Green_Lifecycle: Active; U/M: EA; SizeX_mm: 1.6
C70 = CMP-0074687-3: CAP, CERM, 0.22 µF, 10 V,+/- 10%, X7R, 0603; Manufacturer: Wurth Elektronik; TaMin_C: -55°C; Polarized: N; SizeAreaWB_mm2: 4.68; U/M: EA; Value: 0.22uF; TaMax_C: 125°C; SizeZ_mm: 1.0; SizeX_mm: 1.6; SizeY_mm: 0.8; SizeArea_mm2: 1.28; AEC Category: Q200; ValueDisplayed: 0.22µF
D5 = CMP-0079597-2: Diode, Switching, 75 V, 0.15 A, AEC-Q101, SOD-323; Manufacturer: Diodes Inc.; Value: 75V; Vf_V: 1.25V; Value1: 0.15A; Io_A: 150mA; TJmax_C: 150°C; AEC Category: Q101; AEC Qualified: Y; SizeArea_mm2: 3.645; SizeAreaWB_mm2: 8.695; SizeX_mm: 2.7; SizeY_mm: 1.35; SizeZ_mm: 1
F1 = CMP-0077200-3: Fuse, 30 A, 250 VAC, 100 VDC, SMD; Manufacturer: Littelfuse; VAC_V: 250V; SizeAreaWB_mm2: 61.952; Rtyp_Ohm: 1.93m; SizeArea_mm2: 31.512; MeltingTyp: 916; Irating_A: 30A; SizeZ_mm: 3.12; VDC_V: 100V; SizeX_mm: 10.1; Interrupt_AC: 100A; Interrupt_DC: 50A; Fuse Speed: Fast; Fuse Technology: Board Mount; TaMax_C: 125°C; TaMin_C: -55°C
J5 = CMP-0086764-1: 2 Position Wire to Board Terminal Block Horizontal with Board 0.400" (10.16mm) Through Hole; Manufacturer: Wurth; Current_A: 57A; Voltage_V: 750V; ContactFinish: Zinc; Row_Count: 1
J6-J9 J16 = CMP-0093233-2: 2 Position Wire to Board Terminal Block Horizontal with Board 0.250" (6.35mm) Through Hole; Manufacturer: Wurth Electronics; Current_A: 32A; Conn Gender: Female; Row_Count: 1; ContactFinish: Zinc; SizeZ_mm: 21.6mm; Max Wire Gauge: 10; Min Wire Gauge: 30; Voltage_V: 450V; AEC Qualified: No; Is Female: yes
J10-J12 = CMP-0096350-1: 2 Position Wire to Board Terminal Block Horizontal with Board 0.197" (5.00mm) Through Hole; Manufacturer: Wurth Electronics; Row_Count: 1; AEC Qualified: No; DUT-Pitch_mm: 5mm; Max Wire Gauge: 12; Is Female: yes; ContactFinish: Tin,Nickel; Min Wire Gauge: 30; Current_A: 14A; Voltage_V: 300V; SizeZ_mm: 13.9mm; Conn Gender: Female
J23 = CMP-0075407-2: as J13 on sheet MD085_TCAN284x
L1 = CMP-0087162-1: FIXED IND 2.2UH 16A 2.2 MOHM; Manufacturer: Wurth Electronics; Material: Composite; Isat: 34A; DCR_ohm: 2.42m; SizeZ_mm: 9.1mm; AEC Qualified: No; Symbol Name: SYM-74439369022
Q1 = CMP-0000375-2: Transistor, NPN, 65 V, 0.1 A, SOT-23; Manufacturer: ON Semiconductor; CompType: BJT; PNP: 0; NPN: 1; Vceo_V: 65V; Vcesat1_V: 700mV; Value: 65 V; IcRated_A: 100mA; Value1: 0.1 A; HfeMax: 450; TaMin_C: -55°C; TaMax_C: 150°C; U/M: EA; AEC Category: Q101; SizeArea_mm2: 7.5; SizeAreaWB_mm2: 14; SizeX_mm: 2.5; SizeY_mm: 3; SizeZ_mm: 1.1
Q4 Q8 = CMP-0000713-2: MOSFET, N-CH, 40 V, 100 A, DNK0008A (VSON-CLIP-8); Alternate Manufacturer: None; Manufacturer: Texas Instruments; SizeZ_mm: 1; ChType: N; Value2: 37 nC; Value1: 0.002; VdsMax_V: 40V; SizeX_mm: 6; SizeY_mm: 5; Vgs_V: 20V; Value: 40V; Rdson45_ohm: 2.3m; SizeArea_mm2: 30; AEC Category: Q101; IdsMax_A: 100A; SizeAreaWB_mm2: 56; U/M: EA; QgTyp_nC: 37
Q7 = CMP-0000594-1: MOSFET, N-CH, 30 V, 25 A, DQJ0008A (VSONP-8); Alternate Manufacturer: None; Manufacturer: Texas Instruments; SizeZ_mm: 1.1; ChType: N; Value2: 11.6 nC; Value1: 0.013; VdsMax_V: 30V; SizeX_mm: 6; SizeAreaWB_mm2: 55.2; SizeY_mm: 4.9; Vgs_V: 20V; QgTyp_nC: 11.6; Value: 30V; Rdson45_ohm: 13.3m; SizeArea_mm2: 29.4; AEC Category: Q101; IdsMax_A: 25A; U/M: EA
R32 R33 = CMP-0025886-5: as R67 on sheet MD085_TCAN284x
R34 = CMP-0025885-5: as R64 on sheet MD085_TCAN284x
R47 = CMP-0025899-5: as R65 on sheet MD085_TCAN284x
R51 = CMP-0022918-5: RES, 220, 1%, 0.1 W, 0603; Manufacturer: Yageo; Power_W: 100mW; TempCo: 100 ppm/C; Value_Code: 220R; Value: 220; SizeX_mm: 1.6; SizeY_mm: 0.8; SizeZ_mm: 1; Value2: 0.1W; SizeArea_mm2: 1.28; AEC Qualified: N; VDC_V: 75V; AEC Category: Q200; SizeAreaWB_mm2: 4.68
R57 = CMP-0022895-5: RES, 1.00 k, 1%, 0.1 W, 0603; Manufacturer: Yageo; Power_W: 100mW; TempCo: 100 ppm/C; Value_Code: 1k00; Value: 1.00k; EIA_Code: E96; Res_ohm: 1k; SizeX_mm: 1.6; SizeY_mm: 0.8; SizeZ_mm: 1; Value2: 0.1W; SizeArea_mm2: 1.28; AEC Qualified: N; VDC_V: 75V; AEC Category: Q200; SizeAreaWB_mm2: 4.68
R66 R75 = CMP-0078790-1: RES, 0, 0.05%, 2 W, AEC-Q200 Grade 0, 2512; Manufacturer: Stackpole Electronics Inc; AEC Qualified: Y; AEC Category: Q200; Value: 0; Power_W: 2W
SH1-SH3 = CMP-0075110-1: 1mm Uninsulated Shorting Plug, 10.16mm spacing, TH; PartNumber: D3082-05; Manufacturer: Harwin; CNHeader: False; CompType: Jumper Wire; Green_Lifecycle: Active; Green_REACh: Passed
SH-J21 = CMP-0003761-2: Shunt, 2.54mm, Gold, Black; Manufacturer: Wurth Elektronik
TP20 TP21 = CMP-0055147-2: Test Point, Multipurpose, Red, TH; Manufacturer: Keystone Electronics; CNHeader: FALSE; Green_Lifecycle: Active; Green_REACh: Passed; ContactFinish: Silver; CT: TRUE
TP25 TP26 = CMP-0055148-2: Test Point, Multipurpose, Black, TH; Manufacturer: Keystone Electronics; CNHeader: FALSE; Green_Lifecycle: Active; Green_REACh: Passed; ContactFinish: Silver; CT: TRUE
TP30 = CMP-0003719-1: Testpoint; Manufacturer: Texas Instruments; CompType: Pad
TP31-TP42 TP44 TP46-TP48 = CMP-0055149-2: Test Point, Multipurpose, White, TH; Manufacturer: Keystone Electronics; ContactFinish: Silver; CT: TRUE; CNHeader: FALSE; Green_Lifecycle: Active; Green_REACh: Passed
U2 = CMP-0121851-2: Automotive Multi-function Driver with Integrated Half-bridges &HighSide and Current Sensing & Advanced Diagnostics; Manufacturer: Texas Instruments; SizeZ_mm: 1mm; AEC Qualified: Yes; AEC Grade: Grade 1; Max Supply Voltage: 35V; Min Supply Voltage: 4.5V; Number Of Outputs: 12; Standoff Height: 0mm; TaMax_C: +125°C; TaMin_C: -40°C; TJmax_C: +150°C; AEC Category: Q200; CompType: IC

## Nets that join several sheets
3V3: MD085_XDS110 (J1.4), MD085_M0 (R22.1)
DVDD: MD085_M0 (J2.18), MD085_DRV800x (C43.2 R34.2 U2.21)
GND: MD085_XDS110 (44 pins), MD085_M0 (19 pins), MD085_TCAN284x (29 pins), MD085_DRV800x (55 pins)
PVDD: MD085_M0 (D10.2 R76.2), MD085_TCAN284x (R64.2), MD085_DRV800x (19 pins)
VCC1: MD085_M0 (R21.2), MD085_TCAN284x (7 pins)
BSL_INVOKE: MD085_XDS110 (XDS1.42), MD085_M0 (R23.2 TP8.1)
CAN_RX: MD085_M0 (U1.6), MD085_TCAN284x (U3.24)
CAN_TX: MD085_M0 (U1.5), MD085_TCAN284x (U3.23)
IN2: MD085_M0 (J2.2 TP10.1), MD085_DRV800x (U2.11)
IPROPI: MD085_M0 (J2.14 J3.1 TP16.1), MD085_DRV800x (C68.1 R57.2 U2.17)
MCU_CAN_GFO: MD085_M0 (U1.1), MD085_TCAN284x (U3.25)
MCU_CAN_LRXD: MD085_M0 (U1.57), MD085_TCAN284x (U3.22)
MCU_CAN_LTXD: MD085_M0 (U1.56), MD085_TCAN284x (U3.21)
MCU_CAN_nINT: MD085_M0 (U1.4), MD085_TCAN284x (U3.15)
MCU_CAN_nRST: MD085_M0 (U1.14), MD085_TCAN284x (U3.14)
MCU_CAN_SW: MD085_M0 (U1.3), MD085_TCAN284x (J20.2 U3.16)
MCU_nSCS_CAN: MD085_M0 (TP49.1 U1.29), MD085_TCAN284x (U3.20)
MCU_SCLK: MD085_M0 (J2.11 U1.61), MD085_TCAN284x (U3.17)
MCU_SDI: MD085_M0 (J2.7 U1.60), MD085_TCAN284x (U3.18)
MCU_SDO: MD085_M0 (J2.9 U1.59), MD085_TCAN284x (U3.19)
nSCS_DRV: MD085_M0 (J2.6 TP12.1), MD085_DRV800x (U2.13)
nSLEEP: MD085_M0 (J2.16 TP19.1), MD085_DRV800x (U2.18)
PWM1: MD085_M0 (J2.4 TP11.1), MD085_DRV800x (U2.12)
RST: MD085_XDS110 (J1.10), MD085_M0 (5 pins)
SCLK: MD085_M0 (J2.12 TP15.1), MD085_DRV800x (U2.16)
SDI: MD085_M0 (J2.8 TP13.1), MD085_DRV800x (U2.14)
SDO: MD085_M0 (J2.10 TP14.1), MD085_DRV800x (U2.15)
SWCLK: MD085_XDS110 (J1.14), MD085_M0 (U1.13)
SWDIO: MD085_XDS110 (J1.12), MD085_M0 (U1.12)
UART1_RX: MD085_XDS110 (J1.6), MD085_M0 (U1.53)
UART1_TX: MD085_XDS110 (J1.8), MD085_M0 (U1.52)
WAKE1: MD085_M0 (U1.22), MD085_TCAN284x (J13.3 R43.1 U3.2)
WAKE2: MD085_M0 (U1.21), MD085_TCAN284x (J13.2 R73.1 U3.1)
WAKE3: MD085_M0 (U1.20), MD085_TCAN284x (J13.1 R74.1 U3.32)

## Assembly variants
001: not fitted C49 C50 C51 C52 C53 C54 C55 C56 C57 C59 C60 C61 C64 C65 C66 C68 C71 C72 C73 C87 C88 C89 C90 C91 C92 J21 L1 L2 R21 U3 Y2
